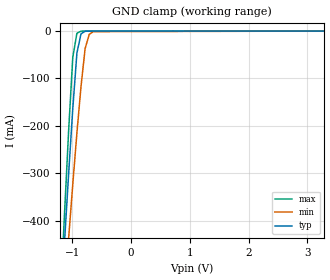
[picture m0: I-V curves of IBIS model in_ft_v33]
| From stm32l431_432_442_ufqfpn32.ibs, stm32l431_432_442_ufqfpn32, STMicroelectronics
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|   Model in_ft_v33
[Model]  in_ft_v33
Model_type Input
Polarity   Non-Inverting
Vinl =   0.990000V
Vinh =   2.310000V
C_comp   0.872570pF   0.859810pF   0.888860pF
[Temperature Range]   25.000000   0.140000k   -40.000000
[Pullup Reference]   3.300000V   2.700000V   3.600000V
[Pulldown Reference]   0.0V   0.0V   0.0V
[POWER Clamp Reference]   3.300000V   2.700000V   3.600000V
[GND Clamp Reference]   0.0V   0.0V   0.0V
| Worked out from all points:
|   GND clamp passes 1 mA (typ) near -0.79 V on its own axis
[GND_clamp]
|Voltage   I(typ)   I(min)   I(max)
-3.3V     -6.646A    -5.438A    -8.156A
-1.2V     -590.6mA   -670.1mA   -565.1mA
-1.13V    -443.4mA   -552mA     -383.5mA
-1.06V    -299.9mA   -435.9mA   -208.6mA
-990mV    -163.6mA   -323mA     -55.25mA
-920mV    -46.37mA   -215.2mA   -4.568mA
-850mV    -5.596mA   -116.8mA   -182.9uA
-780mV    -474.5uA   -36.72mA   -11.93uA
-710mV    -40.03uA   -6.793mA   -4.916uA
-640mV    -6.744uA   -1.168mA   -3.422uA
3.28V     0A         0A         0A
[POWER_clamp]
|Voltage   I(typ)   I(min)   I(max)
-3.28V    0A         0A         0A
0V        0A         0A         0A
